VERSION 5.8 ;
BUSBITCHARS "[]" ;
DIVIDERCHAR "/" ;
UNITS
    DATABASE MICRONS 1000 ;
END UNITS

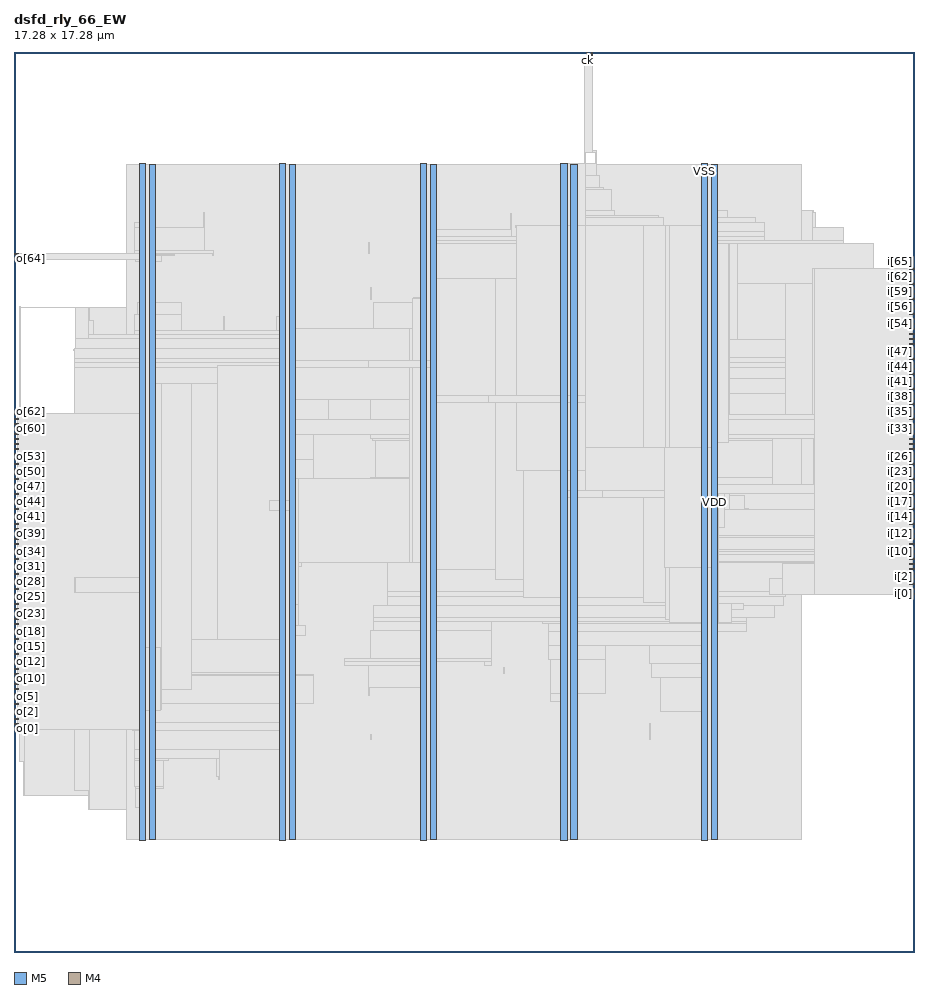
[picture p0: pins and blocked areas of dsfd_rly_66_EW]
MACRO dsfd_rly_66_EW
  FOREIGN dsfd_rly_66_EW 0 0 ;
  CLASS BLOCK ;
  SIZE 17.28 BY 17.28 ;
  PIN ck
    DIRECTION INPUT ;
    USE SIGNAL ;
    PORT
      LAYER M5 ;
        RECT  10.992 17.196 11.016 17.28 ;
    END
  END ck
  PIN i[0]
    DIRECTION INPUT ;
    USE SIGNAL ;
    PORT
      LAYER M4 ;
        RECT  17.196 6.864 17.28 6.888 ;
    END
  END i[0]
  PIN i[10]
    DIRECTION INPUT ;
    USE SIGNAL ;
    PORT
      LAYER M4 ;
        RECT  17.196 7.824 17.28 7.848 ;
    END
  END i[10]
  PIN i[11]
    DIRECTION INPUT ;
    USE SIGNAL ;
    PORT
      LAYER M4 ;
        RECT  17.196 7.92 17.28 7.944 ;
    END
  END i[11]
  PIN i[12]
    DIRECTION INPUT ;
    USE SIGNAL ;
    PORT
      LAYER M4 ;
        RECT  17.196 8.016 17.28 8.04 ;
    END
  END i[12]
  PIN i[13]
    DIRECTION INPUT ;
    USE SIGNAL ;
    PORT
      LAYER M4 ;
        RECT  17.196 8.112 17.28 8.136 ;
    END
  END i[13]
  PIN i[14]
    DIRECTION INPUT ;
    USE SIGNAL ;
    PORT
      LAYER M4 ;
        RECT  17.196 8.208 17.28 8.232 ;
    END
  END i[14]
  PIN i[15]
    DIRECTION INPUT ;
    USE SIGNAL ;
    PORT
      LAYER M4 ;
        RECT  17.196 8.304 17.28 8.328 ;
    END
  END i[15]
  PIN i[16]
    DIRECTION INPUT ;
    USE SIGNAL ;
    PORT
      LAYER M4 ;
        RECT  17.196 8.4 17.28 8.424 ;
    END
  END i[16]
  PIN i[17]
    DIRECTION INPUT ;
    USE SIGNAL ;
    PORT
      LAYER M4 ;
        RECT  17.196 8.496 17.28 8.52 ;
    END
  END i[17]
  PIN i[18]
    DIRECTION INPUT ;
    USE SIGNAL ;
    PORT
      LAYER M4 ;
        RECT  17.196 8.592 17.28 8.616 ;
    END
  END i[18]
  PIN i[19]
    DIRECTION INPUT ;
    USE SIGNAL ;
    PORT
      LAYER M4 ;
        RECT  17.196 8.688 17.28 8.712 ;
    END
  END i[19]
  PIN i[1]
    DIRECTION INPUT ;
    USE SIGNAL ;
    PORT
      LAYER M4 ;
        RECT  17.196 6.96 17.28 6.984 ;
    END
  END i[1]
  PIN i[20]
    DIRECTION INPUT ;
    USE SIGNAL ;
    PORT
      LAYER M4 ;
        RECT  17.196 8.784 17.28 8.808 ;
    END
  END i[20]
  PIN i[21]
    DIRECTION INPUT ;
    USE SIGNAL ;
    PORT
      LAYER M4 ;
        RECT  17.196 8.88 17.28 8.904 ;
    END
  END i[21]
  PIN i[22]
    DIRECTION INPUT ;
    USE SIGNAL ;
    PORT
      LAYER M4 ;
        RECT  17.196 8.976 17.28 9 ;
    END
  END i[22]
  PIN i[23]
    DIRECTION INPUT ;
    USE SIGNAL ;
    PORT
      LAYER M4 ;
        RECT  17.196 9.072 17.28 9.096 ;
    END
  END i[23]
  PIN i[24]
    DIRECTION INPUT ;
    USE SIGNAL ;
    PORT
      LAYER M4 ;
        RECT  17.196 9.168 17.28 9.192 ;
    END
  END i[24]
  PIN i[25]
    DIRECTION INPUT ;
    USE SIGNAL ;
    PORT
      LAYER M4 ;
        RECT  17.196 9.264 17.28 9.288 ;
    END
  END i[25]
  PIN i[26]
    DIRECTION INPUT ;
    USE SIGNAL ;
    PORT
      LAYER M4 ;
        RECT  17.196 9.36 17.28 9.384 ;
    END
  END i[26]
  PIN i[27]
    DIRECTION INPUT ;
    USE SIGNAL ;
    PORT
      LAYER M4 ;
        RECT  17.196 9.456 17.28 9.48 ;
    END
  END i[27]
  PIN i[28]
    DIRECTION INPUT ;
    USE SIGNAL ;
    PORT
      LAYER M4 ;
        RECT  17.196 9.552 17.28 9.576 ;
    END
  END i[28]
  PIN i[29]
    DIRECTION INPUT ;
    USE SIGNAL ;
    PORT
      LAYER M4 ;
        RECT  17.196 9.648 17.28 9.672 ;
    END
  END i[29]
  PIN i[2]
    DIRECTION INPUT ;
    USE SIGNAL ;
    PORT
      LAYER M4 ;
        RECT  17.196 7.056 17.28 7.08 ;
    END
  END i[2]
  PIN i[30]
    DIRECTION INPUT ;
    USE SIGNAL ;
    PORT
      LAYER M4 ;
        RECT  17.196 9.744 17.28 9.768 ;
    END
  END i[30]
  PIN i[31]
    DIRECTION INPUT ;
    USE SIGNAL ;
    PORT
      LAYER M4 ;
        RECT  17.196 9.84 17.28 9.864 ;
    END
  END i[31]
  PIN i[32]
    DIRECTION INPUT ;
    USE SIGNAL ;
    PORT
      LAYER M4 ;
        RECT  17.196 9.936 17.28 9.96 ;
    END
  END i[32]
  PIN i[33]
    DIRECTION INPUT ;
    USE SIGNAL ;
    PORT
      LAYER M4 ;
        RECT  17.196 10.032 17.28 10.056 ;
    END
  END i[33]
  PIN i[34]
    DIRECTION INPUT ;
    USE SIGNAL ;
    PORT
      LAYER M4 ;
        RECT  17.196 10.128 17.28 10.152 ;
    END
  END i[34]
  PIN i[35]
    DIRECTION INPUT ;
    USE SIGNAL ;
    PORT
      LAYER M4 ;
        RECT  17.196 10.224 17.28 10.248 ;
    END
  END i[35]
  PIN i[36]
    DIRECTION INPUT ;
    USE SIGNAL ;
    PORT
      LAYER M4 ;
        RECT  17.196 10.32 17.28 10.344 ;
    END
  END i[36]
  PIN i[37]
    DIRECTION INPUT ;
    USE SIGNAL ;
    PORT
      LAYER M4 ;
        RECT  17.196 10.416 17.28 10.44 ;
    END
  END i[37]
  PIN i[38]
    DIRECTION INPUT ;
    USE SIGNAL ;
    PORT
      LAYER M4 ;
        RECT  17.196 10.512 17.28 10.536 ;
    END
  END i[38]
  PIN i[39]
    DIRECTION INPUT ;
    USE SIGNAL ;
    PORT
      LAYER M4 ;
        RECT  17.196 10.608 17.28 10.632 ;
    END
  END i[39]
  PIN i[3]
    DIRECTION INPUT ;
    USE SIGNAL ;
    PORT
      LAYER M4 ;
        RECT  17.196 7.152 17.28 7.176 ;
    END
  END i[3]
  PIN i[40]
    DIRECTION INPUT ;
    USE SIGNAL ;
    PORT
      LAYER M4 ;
        RECT  17.196 10.704 17.28 10.728 ;
    END
  END i[40]
  PIN i[41]
    DIRECTION INPUT ;
    USE SIGNAL ;
    PORT
      LAYER M4 ;
        RECT  17.196 10.8 17.28 10.824 ;
    END
  END i[41]
  PIN i[42]
    DIRECTION INPUT ;
    USE SIGNAL ;
    PORT
      LAYER M4 ;
        RECT  17.196 10.896 17.28 10.92 ;
    END
  END i[42]
  PIN i[43]
    DIRECTION INPUT ;
    USE SIGNAL ;
    PORT
      LAYER M4 ;
        RECT  17.196 10.992 17.28 11.016 ;
    END
  END i[43]
  PIN i[44]
    DIRECTION INPUT ;
    USE SIGNAL ;
    PORT
      LAYER M4 ;
        RECT  17.196 11.088 17.28 11.112 ;
    END
  END i[44]
  PIN i[45]
    DIRECTION INPUT ;
    USE SIGNAL ;
    PORT
      LAYER M4 ;
        RECT  17.196 11.184 17.28 11.208 ;
    END
  END i[45]
  PIN i[46]
    DIRECTION INPUT ;
    USE SIGNAL ;
    PORT
      LAYER M4 ;
        RECT  17.196 11.28 17.28 11.304 ;
    END
  END i[46]
  PIN i[47]
    DIRECTION INPUT ;
    USE SIGNAL ;
    PORT
      LAYER M4 ;
        RECT  17.196 11.376 17.28 11.4 ;
    END
  END i[47]
  PIN i[48]
    DIRECTION INPUT ;
    USE SIGNAL ;
    PORT
      LAYER M4 ;
        RECT  17.196 11.472 17.28 11.496 ;
    END
  END i[48]
  PIN i[49]
    DIRECTION INPUT ;
    USE SIGNAL ;
    PORT
      LAYER M4 ;
        RECT  17.196 11.568 17.28 11.592 ;
    END
  END i[49]
  PIN i[4]
    DIRECTION INPUT ;
    USE SIGNAL ;
    PORT
      LAYER M4 ;
        RECT  17.196 7.248 17.28 7.272 ;
    END
  END i[4]
  PIN i[50]
    DIRECTION INPUT ;
    USE SIGNAL ;
    PORT
      LAYER M4 ;
        RECT  17.196 11.664 17.28 11.688 ;
    END
  END i[50]
  PIN i[51]
    DIRECTION INPUT ;
    USE SIGNAL ;
    PORT
      LAYER M4 ;
        RECT  17.196 11.76 17.28 11.784 ;
    END
  END i[51]
  PIN i[52]
    DIRECTION INPUT ;
    USE SIGNAL ;
    PORT
      LAYER M4 ;
        RECT  17.196 11.856 17.28 11.88 ;
    END
  END i[52]
  PIN i[53]
    DIRECTION INPUT ;
    USE SIGNAL ;
    PORT
      LAYER M4 ;
        RECT  17.196 11.952 17.28 11.976 ;
    END
  END i[53]
  PIN i[54]
    DIRECTION INPUT ;
    USE SIGNAL ;
    PORT
      LAYER M4 ;
        RECT  17.196 12.048 17.28 12.072 ;
    END
  END i[54]
  PIN i[55]
    DIRECTION INPUT ;
    USE SIGNAL ;
    PORT
      LAYER M4 ;
        RECT  17.196 12.144 17.28 12.168 ;
    END
  END i[55]
  PIN i[56]
    DIRECTION INPUT ;
    USE SIGNAL ;
    PORT
      LAYER M4 ;
        RECT  17.196 12.24 17.28 12.264 ;
    END
  END i[56]
  PIN i[57]
    DIRECTION INPUT ;
    USE SIGNAL ;
    PORT
      LAYER M4 ;
        RECT  17.196 12.336 17.28 12.36 ;
    END
  END i[57]
  PIN i[58]
    DIRECTION INPUT ;
    USE SIGNAL ;
    PORT
      LAYER M4 ;
        RECT  17.196 12.432 17.28 12.456 ;
    END
  END i[58]
  PIN i[59]
    DIRECTION INPUT ;
    USE SIGNAL ;
    PORT
      LAYER M4 ;
        RECT  17.196 12.528 17.28 12.552 ;
    END
  END i[59]
  PIN i[5]
    DIRECTION INPUT ;
    USE SIGNAL ;
    PORT
      LAYER M4 ;
        RECT  17.196 7.344 17.28 7.368 ;
    END
  END i[5]
  PIN i[60]
    DIRECTION INPUT ;
    USE SIGNAL ;
    PORT
      LAYER M4 ;
        RECT  17.196 12.624 17.28 12.648 ;
    END
  END i[60]
  PIN i[61]
    DIRECTION INPUT ;
    USE SIGNAL ;
    PORT
      LAYER M4 ;
        RECT  17.196 12.72 17.28 12.744 ;
    END
  END i[61]
  PIN i[62]
    DIRECTION INPUT ;
    USE SIGNAL ;
    PORT
      LAYER M4 ;
        RECT  17.196 12.816 17.28 12.84 ;
    END
  END i[62]
  PIN i[63]
    DIRECTION INPUT ;
    USE SIGNAL ;
    PORT
      LAYER M4 ;
        RECT  17.196 12.912 17.28 12.936 ;
    END
  END i[63]
  PIN i[64]
    DIRECTION INPUT ;
    USE SIGNAL ;
    PORT
      LAYER M4 ;
        RECT  17.196 13.008 17.28 13.032 ;
    END
  END i[64]
  PIN i[65]
    DIRECTION INPUT ;
    USE SIGNAL ;
    PORT
      LAYER M4 ;
        RECT  17.196 13.104 17.28 13.128 ;
    END
  END i[65]
  PIN i[6]
    DIRECTION INPUT ;
    USE SIGNAL ;
    PORT
      LAYER M4 ;
        RECT  17.196 7.44 17.28 7.464 ;
    END
  END i[6]
  PIN i[7]
    DIRECTION INPUT ;
    USE SIGNAL ;
    PORT
      LAYER M4 ;
        RECT  17.196 7.536 17.28 7.56 ;
    END
  END i[7]
  PIN i[8]
    DIRECTION INPUT ;
    USE SIGNAL ;
    PORT
      LAYER M4 ;
        RECT  17.196 7.632 17.28 7.656 ;
    END
  END i[8]
  PIN i[9]
    DIRECTION INPUT ;
    USE SIGNAL ;
    PORT
      LAYER M4 ;
        RECT  17.196 7.728 17.28 7.752 ;
    END
  END i[9]
  PIN o[0]
    DIRECTION OUTPUT ;
    USE SIGNAL ;
    PORT
      LAYER M4 ;
        RECT  0 4.272 0.084 4.296 ;
    END
  END o[0]
  PIN o[10]
    DIRECTION OUTPUT ;
    USE SIGNAL ;
    PORT
      LAYER M4 ;
        RECT  0 5.232 0.084 5.256 ;
    END
  END o[10]
  PIN o[11]
    DIRECTION OUTPUT ;
    USE SIGNAL ;
    PORT
      LAYER M4 ;
        RECT  0 5.328 0.084 5.352 ;
    END
  END o[11]
  PIN o[12]
    DIRECTION OUTPUT ;
    USE SIGNAL ;
    PORT
      LAYER M4 ;
        RECT  0 5.424 0.084 5.448 ;
    END
  END o[12]
  PIN o[13]
    DIRECTION OUTPUT ;
    USE SIGNAL ;
    PORT
      LAYER M4 ;
        RECT  0 5.52 0.084 5.544 ;
    END
  END o[13]
  PIN o[14]
    DIRECTION OUTPUT ;
    USE SIGNAL ;
    PORT
      LAYER M4 ;
        RECT  0 5.616 0.084 5.64 ;
    END
  END o[14]
  PIN o[15]
    DIRECTION OUTPUT ;
    USE SIGNAL ;
    PORT
      LAYER M4 ;
        RECT  0 5.712 0.084 5.736 ;
    END
  END o[15]
  PIN o[16]
    DIRECTION OUTPUT ;
    USE SIGNAL ;
    PORT
      LAYER M4 ;
        RECT  0 5.808 0.084 5.832 ;
    END
  END o[16]
  PIN o[17]
    DIRECTION OUTPUT ;
    USE SIGNAL ;
    PORT
      LAYER M4 ;
        RECT  0 5.904 0.084 5.928 ;
    END
  END o[17]
  PIN o[18]
    DIRECTION OUTPUT ;
    USE SIGNAL ;
    PORT
      LAYER M4 ;
        RECT  0 6 0.084 6.024 ;
    END
  END o[18]
  PIN o[19]
    DIRECTION OUTPUT ;
    USE SIGNAL ;
    PORT
      LAYER M4 ;
        RECT  0 6.096 0.084 6.12 ;
    END
  END o[19]
  PIN o[1]
    DIRECTION OUTPUT ;
    USE SIGNAL ;
    PORT
      LAYER M4 ;
        RECT  0 4.368 0.084 4.392 ;
    END
  END o[1]
  PIN o[20]
    DIRECTION OUTPUT ;
    USE SIGNAL ;
    PORT
      LAYER M4 ;
        RECT  0 6.192 0.084 6.216 ;
    END
  END o[20]
  PIN o[21]
    DIRECTION OUTPUT ;
    USE SIGNAL ;
    PORT
      LAYER M4 ;
        RECT  0 6.288 0.084 6.312 ;
    END
  END o[21]
  PIN o[22]
    DIRECTION OUTPUT ;
    USE SIGNAL ;
    PORT
      LAYER M4 ;
        RECT  0 6.384 0.084 6.408 ;
    END
  END o[22]
  PIN o[23]
    DIRECTION OUTPUT ;
    USE SIGNAL ;
    PORT
      LAYER M4 ;
        RECT  0 6.48 0.084 6.504 ;
    END
  END o[23]
  PIN o[24]
    DIRECTION OUTPUT ;
    USE SIGNAL ;
    PORT
      LAYER M4 ;
        RECT  0 6.576 0.084 6.6 ;
    END
  END o[24]
  PIN o[25]
    DIRECTION OUTPUT ;
    USE SIGNAL ;
    PORT
      LAYER M4 ;
        RECT  0 6.672 0.084 6.696 ;
    END
  END o[25]
  PIN o[26]
    DIRECTION OUTPUT ;
    USE SIGNAL ;
    PORT
      LAYER M4 ;
        RECT  0 6.768 0.084 6.792 ;
    END
  END o[26]
  PIN o[27]
    DIRECTION OUTPUT ;
    USE SIGNAL ;
    PORT
      LAYER M4 ;
        RECT  0 6.864 0.084 6.888 ;
    END
  END o[27]
  PIN o[28]
    DIRECTION OUTPUT ;
    USE SIGNAL ;
    PORT
      LAYER M4 ;
        RECT  0 6.96 0.084 6.984 ;
    END
  END o[28]
  PIN o[29]
    DIRECTION OUTPUT ;
    USE SIGNAL ;
    PORT
      LAYER M4 ;
        RECT  0 7.056 0.084 7.08 ;
    END
  END o[29]
  PIN o[2]
    DIRECTION OUTPUT ;
    USE SIGNAL ;
    PORT
      LAYER M4 ;
        RECT  0 4.464 0.084 4.488 ;
    END
  END o[2]
  PIN o[30]
    DIRECTION OUTPUT ;
    USE SIGNAL ;
    PORT
      LAYER M4 ;
        RECT  0 7.152 0.084 7.176 ;
    END
  END o[30]
  PIN o[31]
    DIRECTION OUTPUT ;
    USE SIGNAL ;
    PORT
      LAYER M4 ;
        RECT  0 7.248 0.084 7.272 ;
    END
  END o[31]
  PIN o[32]
    DIRECTION OUTPUT ;
    USE SIGNAL ;
    PORT
      LAYER M4 ;
        RECT  0 7.344 0.084 7.368 ;
    END
  END o[32]
  PIN o[33]
    DIRECTION OUTPUT ;
    USE SIGNAL ;
    PORT
      LAYER M4 ;
        RECT  0 7.44 0.084 7.464 ;
    END
  END o[33]
  PIN o[34]
    DIRECTION OUTPUT ;
    USE SIGNAL ;
    PORT
      LAYER M4 ;
        RECT  0 7.536 0.084 7.56 ;
    END
  END o[34]
  PIN o[35]
    DIRECTION OUTPUT ;
    USE SIGNAL ;
    PORT
      LAYER M4 ;
        RECT  0 7.632 0.084 7.656 ;
    END
  END o[35]
  PIN o[36]
    DIRECTION OUTPUT ;
    USE SIGNAL ;
    PORT
      LAYER M4 ;
        RECT  0 7.728 0.084 7.752 ;
    END
  END o[36]
  PIN o[37]
    DIRECTION OUTPUT ;
    USE SIGNAL ;
    PORT
      LAYER M4 ;
        RECT  0 7.824 0.084 7.848 ;
    END
  END o[37]
  PIN o[38]
    DIRECTION OUTPUT ;
    USE SIGNAL ;
    PORT
      LAYER M4 ;
        RECT  0 7.92 0.084 7.944 ;
    END
  END o[38]
  PIN o[39]
    DIRECTION OUTPUT ;
    USE SIGNAL ;
    PORT
      LAYER M4 ;
        RECT  0 8.016 0.084 8.04 ;
    END
  END o[39]
  PIN o[3]
    DIRECTION OUTPUT ;
    USE SIGNAL ;
    PORT
      LAYER M4 ;
        RECT  0 4.56 0.084 4.584 ;
    END
  END o[3]
  PIN o[40]
    DIRECTION OUTPUT ;
    USE SIGNAL ;
    PORT
      LAYER M4 ;
        RECT  0 8.112 0.084 8.136 ;
    END
  END o[40]
  PIN o[41]
    DIRECTION OUTPUT ;
    USE SIGNAL ;
    PORT
      LAYER M4 ;
        RECT  0 8.208 0.084 8.232 ;
    END
  END o[41]
  PIN o[42]
    DIRECTION OUTPUT ;
    USE SIGNAL ;
    PORT
      LAYER M4 ;
        RECT  0 8.304 0.084 8.328 ;
    END
  END o[42]
  PIN o[43]
    DIRECTION OUTPUT ;
    USE SIGNAL ;
    PORT
      LAYER M4 ;
        RECT  0 8.4 0.084 8.424 ;
    END
  END o[43]
  PIN o[44]
    DIRECTION OUTPUT ;
    USE SIGNAL ;
    PORT
      LAYER M4 ;
        RECT  0 8.496 0.084 8.52 ;
    END
  END o[44]
  PIN o[45]
    DIRECTION OUTPUT ;
    USE SIGNAL ;
    PORT
      LAYER M4 ;
        RECT  0 8.592 0.084 8.616 ;
    END
  END o[45]
  PIN o[46]
    DIRECTION OUTPUT ;
    USE SIGNAL ;
    PORT
      LAYER M4 ;
        RECT  0 8.688 0.084 8.712 ;
    END
  END o[46]
  PIN o[47]
    DIRECTION OUTPUT ;
    USE SIGNAL ;
    PORT
      LAYER M4 ;
        RECT  0 8.784 0.084 8.808 ;
    END
  END o[47]
  PIN o[48]
    DIRECTION OUTPUT ;
    USE SIGNAL ;
    PORT
      LAYER M4 ;
        RECT  0 8.88 0.084 8.904 ;
    END
  END o[48]
  PIN o[49]
    DIRECTION OUTPUT ;
    USE SIGNAL ;
    PORT
      LAYER M4 ;
        RECT  0 8.976 0.084 9 ;
    END
  END o[49]
  PIN o[4]
    DIRECTION OUTPUT ;
    USE SIGNAL ;
    PORT
      LAYER M4 ;
        RECT  0 4.656 0.084 4.68 ;
    END
  END o[4]
  PIN o[50]
    DIRECTION OUTPUT ;
    USE SIGNAL ;
    PORT
      LAYER M4 ;
        RECT  0 9.072 0.084 9.096 ;
    END
  END o[50]
  PIN o[51]
    DIRECTION OUTPUT ;
    USE SIGNAL ;
    PORT
      LAYER M4 ;
        RECT  0 9.168 0.084 9.192 ;
    END
  END o[51]
  PIN o[52]
    DIRECTION OUTPUT ;
    USE SIGNAL ;
    PORT
      LAYER M4 ;
        RECT  0 9.264 0.084 9.288 ;
    END
  END o[52]
  PIN o[53]
    DIRECTION OUTPUT ;
    USE SIGNAL ;
    PORT
      LAYER M4 ;
        RECT  0 9.36 0.084 9.384 ;
    END
  END o[53]
  PIN o[54]
    DIRECTION OUTPUT ;
    USE SIGNAL ;
    PORT
      LAYER M4 ;
        RECT  0 9.456 0.084 9.48 ;
    END
  END o[54]
  PIN o[55]
    DIRECTION OUTPUT ;
    USE SIGNAL ;
    PORT
      LAYER M4 ;
        RECT  0 9.552 0.084 9.576 ;
    END
  END o[55]
  PIN o[56]
    DIRECTION OUTPUT ;
    USE SIGNAL ;
    PORT
      LAYER M4 ;
        RECT  0 9.648 0.084 9.672 ;
    END
  END o[56]
  PIN o[57]
    DIRECTION OUTPUT ;
    USE SIGNAL ;
    PORT
      LAYER M4 ;
        RECT  0 9.744 0.084 9.768 ;
    END
  END o[57]
  PIN o[58]
    DIRECTION OUTPUT ;
    USE SIGNAL ;
    PORT
      LAYER M4 ;
        RECT  0 9.84 0.084 9.864 ;
    END
  END o[58]
  PIN o[59]
    DIRECTION OUTPUT ;
    USE SIGNAL ;
    PORT
      LAYER M4 ;
        RECT  0 9.936 0.084 9.96 ;
    END
  END o[59]
  PIN o[5]
    DIRECTION OUTPUT ;
    USE SIGNAL ;
    PORT
      LAYER M4 ;
        RECT  0 4.752 0.084 4.776 ;
    END
  END o[5]
  PIN o[60]
    DIRECTION OUTPUT ;
    USE SIGNAL ;
    PORT
      LAYER M4 ;
        RECT  0 10.032 0.084 10.056 ;
    END
  END o[60]
  PIN o[61]
    DIRECTION OUTPUT ;
    USE SIGNAL ;
    PORT
      LAYER M4 ;
        RECT  0 10.128 0.084 10.152 ;
    END
  END o[61]
  PIN o[62]
    DIRECTION OUTPUT ;
    USE SIGNAL ;
    PORT
      LAYER M4 ;
        RECT  0 10.224 0.084 10.248 ;
    END
  END o[62]
  PIN o[63]
    DIRECTION OUTPUT ;
    USE SIGNAL ;
    PORT
      LAYER M4 ;
        RECT  0 10.32 0.084 10.344 ;
    END
  END o[63]
  PIN o[64]
    DIRECTION OUTPUT ;
    USE SIGNAL ;
    PORT
      LAYER M4 ;
        RECT  0 13.296 0.084 13.32 ;
    END
  END o[64]
  PIN o[65]
    DIRECTION OUTPUT ;
    USE SIGNAL ;
    PORT
      LAYER M4 ;
        RECT  0 13.392 0.084 13.416 ;
    END
  END o[65]
  PIN o[6]
    DIRECTION OUTPUT ;
    USE SIGNAL ;
    PORT
      LAYER M4 ;
        RECT  0 4.848 0.084 4.872 ;
    END
  END o[6]
  PIN o[7]
    DIRECTION OUTPUT ;
    USE SIGNAL ;
    PORT
      LAYER M4 ;
        RECT  0 4.944 0.084 4.968 ;
    END
  END o[7]
  PIN o[8]
    DIRECTION OUTPUT ;
    USE SIGNAL ;
    PORT
      LAYER M4 ;
        RECT  0 5.04 0.084 5.064 ;
    END
  END o[8]
  PIN o[9]
    DIRECTION OUTPUT ;
    USE SIGNAL ;
    PORT
      LAYER M4 ;
        RECT  0 5.136 0.084 5.16 ;
    END
  END o[9]
  PIN rs
    DIRECTION INPUT ;
    USE SIGNAL ;
    PORT
      LAYER M5 ;
        RECT  11.088 17.196 11.112 17.28 ;
    END
  END rs
  PIN VDD
    DIRECTION INOUT ;
    USE POWER ;
    PORT
      LAYER M5 ;
        RECT  13.392 2.151 13.512 15.129 ;
        RECT  10.692 2.151 10.812 15.129 ;
        RECT  7.992 2.151 8.112 15.129 ;
        RECT  5.292 2.151 5.412 15.129 ;
        RECT  2.592 2.151 2.712 15.129 ;
    END
  END VDD
  PIN VSS
    DIRECTION INOUT ;
    USE GROUND ;
    PORT
      LAYER M5 ;
        RECT  13.2 2.137 13.32 15.143 ;
        RECT  10.5 2.137 10.62 15.143 ;
        RECT  7.8 2.137 7.92 15.143 ;
        RECT  5.1 2.137 5.22 15.143 ;
        RECT  2.4 2.137 2.52 15.143 ;
    END
  END VSS
  # OT_OBS_CLOSED layer=M5 d_um=1.536 added=5
  OBS
    LAYER RVTN ;
     RECT  2.16 2.16 15.12 2.295 ;
     RECT  2.16 2.565 15.12 2.835 ;
     RECT  2.16 3.105 15.12 3.375 ;
     RECT  2.16 3.645 15.12 3.915 ;
     RECT  2.16 4.185 15.12 4.455 ;
     RECT  2.16 4.725 15.12 4.995 ;
     RECT  2.16 5.265 15.12 5.535 ;
     RECT  2.16 5.805 15.12 6.075 ;
     RECT  2.16 6.345 15.12 6.615 ;
     RECT  2.16 6.885 15.12 7.155 ;
     RECT  2.16 7.425 15.12 7.695 ;
     RECT  2.16 7.965 15.12 8.235 ;
     RECT  2.16 8.505 15.12 8.775 ;
     RECT  2.16 9.045 15.12 9.315 ;
     RECT  2.16 9.585 15.12 9.855 ;
     RECT  2.16 10.125 15.12 10.395 ;
     RECT  2.16 10.665 15.12 10.935 ;
     RECT  2.16 11.205 15.12 11.475 ;
     RECT  2.16 11.745 15.12 12.015 ;
     RECT  2.16 12.285 15.12 12.555 ;
     RECT  2.16 12.825 15.12 13.095 ;
     RECT  2.16 13.365 15.12 13.635 ;
     RECT  2.16 13.905 15.12 14.175 ;
     RECT  2.16 14.445 15.12 14.715 ;
     RECT  2.16 14.985 15.12 15.12 ;
    LAYER RVTP ;
     RECT  2.16 2.295 15.12 2.565 ;
     RECT  2.16 2.835 15.12 3.105 ;
     RECT  2.16 3.375 15.12 3.645 ;
     RECT  2.16 3.915 15.12 4.185 ;
     RECT  2.16 4.455 15.12 4.725 ;
     RECT  2.16 4.995 15.12 5.265 ;
     RECT  2.16 5.535 15.12 5.805 ;
     RECT  2.16 6.075 15.12 6.345 ;
     RECT  2.16 6.615 15.12 6.885 ;
     RECT  2.16 7.155 15.12 7.425 ;
     RECT  2.16 7.695 15.12 7.965 ;
     RECT  2.16 8.235 15.12 8.505 ;
     RECT  2.16 8.775 15.12 9.045 ;
     RECT  2.16 9.315 15.12 9.585 ;
     RECT  2.16 9.855 15.12 10.125 ;
     RECT  2.16 10.395 15.12 10.665 ;
     RECT  2.16 10.935 15.12 11.205 ;
     RECT  2.16 11.475 15.12 11.745 ;
     RECT  2.16 12.015 15.12 12.285 ;
     RECT  2.16 12.555 15.12 12.825 ;
     RECT  2.16 13.095 15.12 13.365 ;
     RECT  2.16 13.635 15.12 13.905 ;
     RECT  2.16 14.175 15.12 14.445 ;
     RECT  2.16 14.715 15.12 14.985 ;
    LAYER M1 ;
     RECT  2.16 2.151 15.12 15.129 ;
    LAYER M2 ;
     RECT  0.103 3.654 0.139 3.672 ;
     RECT  0.103 4.536 0.139 4.554 ;
     RECT  0.139 3.654 0.175 4.554 ;
     RECT  0.103 7.821 0.211 7.839 ;
     RECT  0.211 7.704 0.311 8.226 ;
     RECT  0.311 7.704 0.347 7.839 ;
     RECT  1.147 11.556 1.183 11.574 ;
     RECT  0.103 12.366 1.183 12.384 ;
     RECT  0.175 3.006 1.435 4.554 ;
     RECT  1.435 2.736 2.16 4.554 ;
     RECT  1.183 11.556 2.16 12.384 ;
     RECT  2.16 2.151 15.12 15.129 ;
     RECT  15.12 6.93 15.359 14.238 ;
     RECT  15.359 6.93 15.395 14.202 ;
     RECT  15.395 6.93 15.431 13.896 ;
     RECT  15.431 7.164 15.935 13.896 ;
     RECT  15.935 7.164 15.971 13.59 ;
     RECT  15.971 12.636 16.475 13.59 ;
     RECT  15.971 8.586 16.511 11.889 ;
     RECT  16.475 13.572 16.511 13.59 ;
     RECT  15.971 7.164 16.547 7.794 ;
     RECT  16.511 9.36 16.547 11.889 ;
     RECT  16.547 7.2 16.619 7.794 ;
     RECT  16.619 7.776 17.195 7.794 ;
     RECT  16.511 8.586 17.195 8.604 ;
     RECT  16.547 9.36 17.195 10.998 ;
     RECT  16.547 11.871 17.195 11.889 ;
     RECT  16.475 12.636 17.195 12.654 ;
    LAYER M3 ;
     RECT  2.415 2.143 2.505 2.413 ;
     RECT  5.115 2.143 5.205 2.413 ;
     RECT  7.815 2.143 7.905 2.413 ;
     RECT  10.515 2.143 10.605 2.413 ;
     RECT  13.215 2.143 13.305 2.413 ;
     RECT  2.415 2.413 2.697 2.767 ;
     RECT  1.44 2.731 1.458 3.109 ;
     RECT  2.34 2.767 2.697 3.145 ;
     RECT  2.34 3.145 2.862 3.181 ;
     RECT  3.924 3.307 3.942 3.379 ;
     RECT  0.18 3.001 0.198 3.649 ;
     RECT  2.304 3.181 2.862 3.685 ;
     RECT  2.304 3.685 2.97 3.721 ;
     RECT  3.888 3.379 3.942 3.721 ;
     RECT  2.304 3.721 3.942 3.883 ;
     RECT  5.115 2.413 5.397 3.883 ;
     RECT  6.84 4.081 6.858 4.181 ;
     RECT  2.304 3.883 5.397 4.261 ;
     RECT  12.204 4.081 12.222 4.379 ;
     RECT  2.268 4.261 5.397 4.397 ;
     RECT  0.108 3.649 0.198 4.459 ;
     RECT  1.152 3.109 1.458 4.459 ;
     RECT  0.108 4.459 1.458 4.589 ;
     RECT  13.215 2.413 13.497 4.621 ;
     RECT  2.304 4.397 5.397 4.765 ;
     RECT  10.515 2.413 10.797 4.801 ;
     RECT  1.152 4.589 1.458 4.877 ;
     RECT  10.296 4.801 10.797 4.963 ;
     RECT  6.804 4.927 6.822 5.071 ;
     RECT  7.815 2.413 8.097 5.071 ;
     RECT  1.152 4.877 1.17 5.261 ;
     RECT  12.42 4.621 13.497 5.269 ;
     RECT  2.304 4.765 5.742 5.305 ;
     RECT  2.268 5.305 5.742 5.333 ;
     RECT  2.268 5.333 5.397 5.357 ;
     RECT  9.396 5.341 9.414 5.459 ;
     RECT  6.804 5.071 8.097 5.503 ;
     RECT  12.24 5.269 13.497 5.539 ;
     RECT  6.336 5.503 8.097 5.575 ;
     RECT  9.036 5.503 9.162 5.575 ;
     RECT  10.296 4.963 11.358 5.611 ;
     RECT  6.336 5.575 9.162 5.639 ;
     RECT  0.108 4.589 0.198 5.645 ;
     RECT  10.26 5.611 11.358 5.881 ;
     RECT  12.204 5.539 13.497 5.881 ;
     RECT  0.144 5.645 0.198 5.933 ;
     RECT  2.304 5.357 5.397 6.079 ;
     RECT  10.26 5.881 13.497 6.151 ;
     RECT  6.84 5.639 9.162 6.179 ;
     RECT  2.304 6.079 5.598 6.269 ;
     RECT  10.26 6.151 14.058 6.313 ;
     RECT  6.912 6.179 9.162 6.349 ;
     RECT  10.152 6.313 14.058 6.349 ;
     RECT  6.912 6.349 14.058 6.421 ;
     RECT  0.144 5.933 0.162 6.509 ;
     RECT  6.912 6.421 14.598 6.647 ;
     RECT  7.164 6.647 14.598 6.655 ;
     RECT  7.164 6.655 14.778 6.817 ;
     RECT  7.164 6.817 14.814 6.925 ;
     RECT  1.152 6.955 1.17 7.051 ;
     RECT  1.152 7.051 1.278 7.133 ;
     RECT  16.524 7.159 16.542 7.195 ;
     RECT  2.304 6.269 5.454 7.231 ;
     RECT  16.524 7.195 16.614 7.373 ;
     RECT  2.196 7.231 5.454 7.393 ;
     RECT  2.196 7.393 5.526 7.469 ;
     RECT  7.164 6.925 15.426 7.483 ;
     RECT  6.84 7.483 15.426 7.501 ;
     RECT  0.288 7.243 0.306 7.531 ;
     RECT  0.288 7.531 0.342 7.627 ;
     RECT  6.588 7.501 15.426 7.627 ;
     RECT  6.588 7.627 15.966 7.699 ;
     RECT  0.216 7.627 0.342 7.723 ;
     RECT  6.516 7.699 15.966 7.735 ;
     RECT  0.108 7.723 0.342 7.844 ;
     RECT  2.304 7.469 5.526 7.915 ;
     RECT  6.444 7.735 15.966 7.961 ;
     RECT  0.144 7.844 0.342 7.963 ;
     RECT  1.26 7.133 1.278 7.963 ;
     RECT  6.804 7.961 15.966 7.997 ;
     RECT  0.144 7.963 0.414 8.141 ;
     RECT  2.304 7.915 5.67 8.473 ;
     RECT  6.84 7.997 15.966 8.491 ;
     RECT  17.172 7.531 17.19 8.491 ;
     RECT  1.152 7.963 1.278 8.525 ;
     RECT  2.304 8.473 5.814 8.587 ;
     RECT  6.84 8.491 17.19 8.807 ;
     RECT  0.144 8.141 0.342 8.813 ;
     RECT  0.144 8.813 0.234 8.909 ;
     RECT  1.728 8.587 5.814 8.969 ;
     RECT  6.84 8.807 16.002 8.969 ;
     RECT  6.84 8.969 14.562 9.101 ;
     RECT  1.728 8.969 5.742 9.451 ;
     RECT  0.108 9.067 0.126 9.739 ;
     RECT  6.948 9.101 14.562 9.823 ;
     RECT  6.876 9.823 14.562 9.859 ;
     RECT  15.372 8.969 16.002 9.859 ;
     RECT  1.152 9.451 5.742 9.931 ;
     RECT  6.84 9.859 16.002 9.931 ;
     RECT  1.152 9.931 16.002 10.229 ;
     RECT  0.108 9.739 0.162 10.253 ;
     RECT  17.136 8.807 17.19 10.315 ;
     RECT  6.84 10.229 16.002 10.603 ;
     RECT  17.1 10.315 17.19 10.603 ;
     RECT  6.84 10.603 17.19 11.003 ;
     RECT  1.152 10.229 6.03 11.227 ;
     RECT  6.84 11.003 16.542 11.227 ;
     RECT  1.152 11.227 16.542 11.309 ;
     RECT  1.152 11.309 5.958 11.399 ;
     RECT  6.696 11.309 15.966 11.405 ;
     RECT  1.152 11.399 5.397 11.579 ;
     RECT  1.188 11.579 5.397 11.777 ;
     RECT  6.84 11.405 15.966 11.777 ;
     RECT  1.44 11.777 5.397 11.849 ;
     RECT  2.304 11.849 5.397 11.939 ;
     RECT  1.44 11.849 1.53 12.119 ;
     RECT  4.032 11.939 4.05 12.209 ;
     RECT  5.04 11.939 5.397 12.209 ;
     RECT  2.304 11.939 3.222 12.245 ;
     RECT  1.44 12.119 1.458 12.353 ;
     RECT  0.108 10.253 0.126 12.389 ;
     RECT  2.376 12.245 3.222 12.479 ;
     RECT  6.912 11.777 15.966 12.479 ;
     RECT  7.668 12.479 15.966 12.523 ;
     RECT  17.172 11.851 17.19 12.523 ;
     RECT  7.668 12.523 17.19 12.557 ;
     RECT  7.815 12.557 17.19 12.659 ;
     RECT  6.84 12.523 6.858 12.749 ;
     RECT  2.415 12.479 2.697 13.261 ;
     RECT  2.34 13.261 2.826 13.369 ;
     RECT  2.34 13.369 3.078 13.387 ;
     RECT  2.304 13.387 3.078 13.405 ;
     RECT  3.816 13.369 3.834 13.405 ;
     RECT  2.304 13.405 3.834 13.469 ;
     RECT  7.815 12.659 16.506 13.595 ;
     RECT  6.804 13.405 6.822 13.631 ;
     RECT  7.815 13.595 15.93 13.667 ;
     RECT  7.815 13.667 14.418 13.739 ;
     RECT  10.296 13.739 14.418 13.829 ;
     RECT  7.815 13.739 9.558 13.865 ;
     RECT  10.296 13.829 12.474 13.865 ;
     RECT  2.304 13.469 3.654 13.901 ;
     RECT  10.332 13.865 12.474 13.901 ;
     RECT  15.336 13.667 15.93 13.901 ;
     RECT  2.304 13.901 2.697 14.009 ;
     RECT  13.215 13.829 14.418 14.009 ;
     RECT  10.515 13.901 12.474 14.099 ;
     RECT  13.215 14.009 14.238 14.099 ;
     RECT  10.515 14.099 12.366 14.135 ;
     RECT  9.54 13.865 9.558 14.171 ;
     RECT  3.636 13.901 3.654 14.207 ;
     RECT  15.336 13.901 15.39 14.207 ;
     RECT  10.515 14.135 11.538 14.243 ;
     RECT  13.215 14.099 13.698 14.243 ;
     RECT  15.336 14.207 15.354 14.243 ;
     RECT  10.515 14.243 11.466 14.639 ;
     RECT  10.515 14.639 11.322 14.675 ;
     RECT  2.415 14.009 2.697 14.867 ;
     RECT  5.115 12.209 5.397 14.867 ;
     RECT  7.815 13.865 8.097 14.867 ;
     RECT  13.215 14.243 13.497 14.867 ;
     RECT  10.515 14.675 11.25 14.909 ;
     RECT  2.415 14.867 2.505 15.137 ;
     RECT  5.115 14.867 5.205 15.137 ;
     RECT  7.815 14.867 7.905 15.137 ;
     RECT  10.515 14.909 11.178 15.137 ;
     RECT  13.215 14.867 13.305 15.137 ;
     RECT  11.16 15.137 11.178 15.389 ;
     RECT  11.052 17.035 11.07 17.165 ;
    LAYER M4 ;
     RECT  0.06 4.272 2.408 10.344 ;
     RECT  0.06 13.296 2.408 13.416 ;
     RECT  2.408 2.148 2.512 15.132 ;
     RECT  2.512 2.418 2.704 14.862 ;
     RECT  2.704 4.656 2.837 10.92 ;
     RECT  2.837 5.04 3.413 10.92 ;
     RECT  3.413 6 3.913 10.92 ;
     RECT  3.913 6 5.101 11.256 ;
     RECT  5.101 6 5.108 11.976 ;
     RECT  5.108 2.148 5.212 15.132 ;
     RECT  5.212 2.418 5.404 14.862 ;
     RECT  5.404 6.672 5.465 9.096 ;
     RECT  5.465 7.488 7.585 9.096 ;
     RECT  5.404 10.608 7.585 11.976 ;
     RECT  7.585 7.488 7.657 11.976 ;
     RECT  7.657 7.488 7.801 12.552 ;
     RECT  7.801 7.344 7.808 12.552 ;
     RECT  7.808 2.148 7.912 15.132 ;
     RECT  7.912 2.418 8.104 14.862 ;
     RECT  8.104 7.344 9.241 12.936 ;
     RECT  9.241 7.152 9.781 12.936 ;
     RECT  9.781 6.816 10.508 12.936 ;
     RECT  9.637 13.92 10.508 13.944 ;
     RECT  10.508 2.148 10.612 15.132 ;
     RECT  10.612 2.418 10.804 15.132 ;
     RECT  10.933 17.04 10.981 17.064 ;
     RECT  10.981 17.04 11.081 17.16 ;
     RECT  11.077 15.36 11.189 15.384 ;
     RECT  10.804 6.816 12.085 13.944 ;
     RECT  12.085 6.72 12.517 13.944 ;
     RECT  12.517 6.384 12.589 13.944 ;
     RECT  12.589 6.336 13.208 13.944 ;
     RECT  13.208 2.148 13.312 15.132 ;
     RECT  13.312 2.418 13.504 14.862 ;
     RECT  13.504 6.336 13.529 8.808 ;
     RECT  13.529 8.16 13.637 8.808 ;
     RECT  13.504 9.792 13.709 13.608 ;
     RECT  13.637 8.496 13.745 8.808 ;
     RECT  13.709 10.32 13.745 13.608 ;
     RECT  13.529 6.336 13.781 6.696 ;
     RECT  13.745 11.76 13.889 13.608 ;
     RECT  13.781 6.576 13.997 6.696 ;
     RECT  13.745 8.496 14.033 8.76 ;
     RECT  14.033 8.496 14.105 8.52 ;
     RECT  14.497 6.864 14.749 7.176 ;
     RECT  13.745 10.32 14.821 10.728 ;
     RECT  13.889 11.76 14.821 12.84 ;
     RECT  14.821 10.32 15.325 12.84 ;
     RECT  14.749 6.864 15.361 7.464 ;
     RECT  15.325 10.32 15.361 13.128 ;
     RECT  15.361 6.864 17.244 13.128 ;
    LAYER M5 ;
     RECT  2.4 2.137 2.52 2.151 ;
     RECT  5.1 2.137 5.22 2.151 ;
     RECT  7.8 2.137 7.92 2.151 ;
     RECT  10.5 2.137 10.62 2.151 ;
     RECT  13.2 2.137 13.32 2.151 ;
     RECT  2.4 2.151 2.712 4.645 ;
     RECT  2.4 4.645 2.808 5.843 ;
     RECT  1.152 6.901 1.176 7.187 ;
     RECT  13.2 2.151 13.512 7.381 ;
     RECT  5.1 2.151 5.412 8.485 ;
     RECT  4.896 8.485 5.412 8.675 ;
     RECT  10.5 2.151 10.812 8.725 ;
     RECT  10.5 8.725 11.304 8.867 ;
     RECT  10.5 8.867 10.968 9.253 ;
     RECT  12.48 7.381 13.512 9.683 ;
     RECT  9.648 9.253 10.968 10.549 ;
     RECT  9.12 10.549 10.968 10.691 ;
     RECT  7.8 2.151 8.112 11.221 ;
     RECT  6.816 11.221 8.112 11.363 ;
     RECT  9.648 10.691 10.968 13.955 ;
     RECT  2.4 5.843 2.712 15.129 ;
     RECT  5.1 8.675 5.412 15.129 ;
     RECT  7.8 11.363 8.112 15.129 ;
     RECT  13.2 9.683 13.512 15.129 ;
     RECT  2.4 15.129 2.52 15.143 ;
     RECT  5.1 15.129 5.22 15.143 ;
     RECT  7.8 15.129 7.92 15.143 ;
     RECT  10.5 13.955 10.968 15.143 ;
     RECT  13.2 15.129 13.32 15.143 ;
     RECT  10.944 15.143 10.968 15.349 ;
     RECT  10.944 15.349 11.112 17.075 ;
     RECT  10.992 17.075 11.112 17.232 ;
     RECT  1.176 6.901 2.4 7.187 ;
     RECT  11.304 8.725 12.48 8.867 ;
     RECT  10.968 8.867 12.48 9.683 ;
     RECT  8.112 10.549 9.12 10.691 ;
     RECT  5.412 11.221 6.816 11.363 ;
  END
END dsfd_rly_66_EW
END LIBRARY
